VERSION 5.7 ;
  NOWIREEXTENSIONATPIN ON ;
  DIVIDERCHAR "/" ;
  BUSBITCHARS "[]" ;
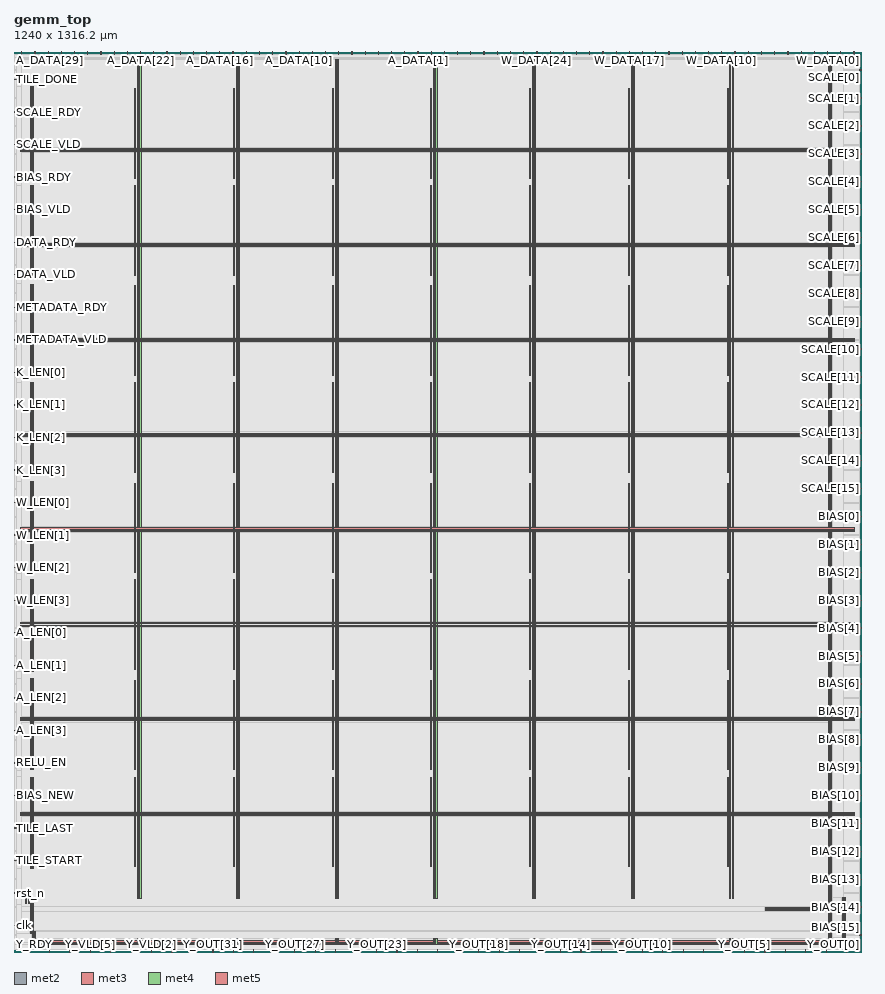
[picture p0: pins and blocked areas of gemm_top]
MACRO gemm_top
  CLASS BLOCK ;
  FOREIGN gemm_top ;
  ORIGIN 0.000 0.000 ;
  SIZE 1240.000 BY 1316.200 ;
  PIN A_DATA[0]
    DIRECTION INPUT ;
    USE SIGNAL ;
    ANTENNAGATEAREA 0.213000 ;
    PORT
      LAYER met2 ;
        RECT 610.050 1312.200 610.330 1316.200 ;
    END
  END A_DATA[0]
  PIN A_DATA[10]
    DIRECTION INPUT ;
    USE SIGNAL ;
    ANTENNAGATEAREA 0.426000 ;
    PORT
      LAYER met2 ;
        RECT 416.850 1312.200 417.130 1316.200 ;
    END
  END A_DATA[10]
  PIN A_DATA[11]
    DIRECTION INPUT ;
    USE SIGNAL ;
    ANTENNAGATEAREA 0.426000 ;
    PORT
      LAYER met2 ;
        RECT 397.530 1312.200 397.810 1316.200 ;
    END
  END A_DATA[11]
  PIN A_DATA[12]
    DIRECTION INPUT ;
    USE SIGNAL ;
    ANTENNAGATEAREA 0.426000 ;
    PORT
      LAYER met2 ;
        RECT 378.210 1312.200 378.490 1316.200 ;
    END
  END A_DATA[12]
  PIN A_DATA[13]
    DIRECTION INPUT ;
    USE SIGNAL ;
    ANTENNAGATEAREA 0.426000 ;
    PORT
      LAYER met2 ;
        RECT 358.890 1312.200 359.170 1316.200 ;
    END
  END A_DATA[13]
  PIN A_DATA[14]
    DIRECTION INPUT ;
    USE SIGNAL ;
    ANTENNAGATEAREA 0.426000 ;
    PORT
      LAYER met2 ;
        RECT 339.570 1312.200 339.850 1316.200 ;
    END
  END A_DATA[14]
  PIN A_DATA[15]
    DIRECTION INPUT ;
    USE SIGNAL ;
    ANTENNAGATEAREA 0.426000 ;
    PORT
      LAYER met2 ;
        RECT 320.250 1312.200 320.530 1316.200 ;
    END
  END A_DATA[15]
  PIN A_DATA[16]
    DIRECTION INPUT ;
    USE SIGNAL ;
    ANTENNAGATEAREA 0.426000 ;
    PORT
      LAYER met2 ;
        RECT 300.930 1312.200 301.210 1316.200 ;
    END
  END A_DATA[16]
  PIN A_DATA[17]
    DIRECTION INPUT ;
    USE SIGNAL ;
    ANTENNAGATEAREA 0.426000 ;
    PORT
      LAYER met2 ;
        RECT 281.610 1312.200 281.890 1316.200 ;
    END
  END A_DATA[17]
  PIN A_DATA[18]
    DIRECTION INPUT ;
    USE SIGNAL ;
    ANTENNAGATEAREA 0.426000 ;
    PORT
      LAYER met2 ;
        RECT 262.290 1312.200 262.570 1316.200 ;
    END
  END A_DATA[18]
  PIN A_DATA[19]
    DIRECTION INPUT ;
    USE SIGNAL ;
    ANTENNAGATEAREA 0.426000 ;
    PORT
      LAYER met2 ;
        RECT 242.970 1312.200 243.250 1316.200 ;
    END
  END A_DATA[19]
  PIN A_DATA[1]
    DIRECTION INPUT ;
    USE SIGNAL ;
    ANTENNAGATEAREA 0.213000 ;
    PORT
      LAYER met2 ;
        RECT 590.730 1312.200 591.010 1316.200 ;
    END
  END A_DATA[1]
  PIN A_DATA[20]
    DIRECTION INPUT ;
    USE SIGNAL ;
    ANTENNAGATEAREA 0.426000 ;
    PORT
      LAYER met2 ;
        RECT 223.650 1312.200 223.930 1316.200 ;
    END
  END A_DATA[20]
  PIN A_DATA[21]
    DIRECTION INPUT ;
    USE SIGNAL ;
    ANTENNAGATEAREA 0.426000 ;
    PORT
      LAYER met2 ;
        RECT 204.330 1312.200 204.610 1316.200 ;
    END
  END A_DATA[21]
  PIN A_DATA[22]
    DIRECTION INPUT ;
    USE SIGNAL ;
    ANTENNAGATEAREA 0.426000 ;
    PORT
      LAYER met2 ;
        RECT 185.010 1312.200 185.290 1316.200 ;
    END
  END A_DATA[22]
  PIN A_DATA[23]
    DIRECTION INPUT ;
    USE SIGNAL ;
    ANTENNAGATEAREA 0.426000 ;
    PORT
      LAYER met2 ;
        RECT 165.690 1312.200 165.970 1316.200 ;
    END
  END A_DATA[23]
  PIN A_DATA[24]
    DIRECTION INPUT ;
    USE SIGNAL ;
    ANTENNAGATEAREA 0.742500 ;
    PORT
      LAYER met2 ;
        RECT 146.370 1312.200 146.650 1316.200 ;
    END
  END A_DATA[24]
  PIN A_DATA[25]
    DIRECTION INPUT ;
    USE SIGNAL ;
    ANTENNAGATEAREA 0.742500 ;
    PORT
      LAYER met2 ;
        RECT 127.050 1312.200 127.330 1316.200 ;
    END
  END A_DATA[25]
  PIN A_DATA[26]
    DIRECTION INPUT ;
    USE SIGNAL ;
    ANTENNAGATEAREA 0.495000 ;
    PORT
      LAYER met2 ;
        RECT 107.730 1312.200 108.010 1316.200 ;
    END
  END A_DATA[26]
  PIN A_DATA[27]
    DIRECTION INPUT ;
    USE SIGNAL ;
    ANTENNAGATEAREA 0.495000 ;
    PORT
      LAYER met2 ;
        RECT 88.410 1312.200 88.690 1316.200 ;
    END
  END A_DATA[27]
  PIN A_DATA[28]
    DIRECTION INPUT ;
    USE SIGNAL ;
    ANTENNAGATEAREA 0.742500 ;
    PORT
      LAYER met2 ;
        RECT 69.090 1312.200 69.370 1316.200 ;
    END
  END A_DATA[28]
  PIN A_DATA[29]
    DIRECTION INPUT ;
    USE SIGNAL ;
    ANTENNAGATEAREA 0.742500 ;
    PORT
      LAYER met2 ;
        RECT 49.770 1312.200 50.050 1316.200 ;
    END
  END A_DATA[29]
  PIN A_DATA[2]
    DIRECTION INPUT ;
    USE SIGNAL ;
    ANTENNAGATEAREA 0.213000 ;
    PORT
      LAYER met2 ;
        RECT 571.410 1312.200 571.690 1316.200 ;
    END
  END A_DATA[2]
  PIN A_DATA[30]
    DIRECTION INPUT ;
    USE SIGNAL ;
    ANTENNAGATEAREA 0.742500 ;
    PORT
      LAYER met2 ;
        RECT 30.450 1312.200 30.730 1316.200 ;
    END
  END A_DATA[30]
  PIN A_DATA[31]
    DIRECTION INPUT ;
    USE SIGNAL ;
    ANTENNAGATEAREA 0.742500 ;
    PORT
      LAYER met2 ;
        RECT 11.130 1312.200 11.410 1316.200 ;
    END
  END A_DATA[31]
  PIN A_DATA[3]
    DIRECTION INPUT ;
    USE SIGNAL ;
    ANTENNAGATEAREA 0.213000 ;
    PORT
      LAYER met2 ;
        RECT 552.090 1312.200 552.370 1316.200 ;
    END
  END A_DATA[3]
  PIN A_DATA[4]
    DIRECTION INPUT ;
    USE SIGNAL ;
    ANTENNAGATEAREA 0.247500 ;
    PORT
      LAYER met2 ;
        RECT 532.770 1312.200 533.050 1316.200 ;
    END
  END A_DATA[4]
  PIN A_DATA[5]
    DIRECTION INPUT ;
    USE SIGNAL ;
    ANTENNAGATEAREA 0.247500 ;
    PORT
      LAYER met2 ;
        RECT 513.450 1312.200 513.730 1316.200 ;
    END
  END A_DATA[5]
  PIN A_DATA[6]
    DIRECTION INPUT ;
    USE SIGNAL ;
    ANTENNAGATEAREA 0.213000 ;
    PORT
      LAYER met2 ;
        RECT 494.130 1312.200 494.410 1316.200 ;
    END
  END A_DATA[6]
  PIN A_DATA[7]
    DIRECTION INPUT ;
    USE SIGNAL ;
    ANTENNAGATEAREA 0.213000 ;
    PORT
      LAYER met2 ;
        RECT 474.810 1312.200 475.090 1316.200 ;
    END
  END A_DATA[7]
  PIN A_DATA[8]
    DIRECTION INPUT ;
    USE SIGNAL ;
    ANTENNAGATEAREA 0.426000 ;
    PORT
      LAYER met2 ;
        RECT 455.490 1312.200 455.770 1316.200 ;
    END
  END A_DATA[8]
  PIN A_DATA[9]
    DIRECTION INPUT ;
    USE SIGNAL ;
    ANTENNAGATEAREA 0.426000 ;
    PORT
      LAYER met2 ;
        RECT 436.170 1312.200 436.450 1316.200 ;
    END
  END A_DATA[9]
  PIN A_LEN[0]
    DIRECTION INPUT ;
    USE SIGNAL ;
    ANTENNAGATEAREA 0.213000 ;
    PORT
      LAYER met3 ;
        RECT 0.000 466.520 4.000 467.120 ;
    END
  END A_LEN[0]
  PIN A_LEN[1]
    DIRECTION INPUT ;
    USE SIGNAL ;
    ANTENNAGATEAREA 0.159000 ;
    PORT
      LAYER met3 ;
        RECT 0.000 418.920 4.000 419.520 ;
    END
  END A_LEN[1]
  PIN A_LEN[2]
    DIRECTION INPUT ;
    USE SIGNAL ;
    ANTENNAGATEAREA 0.213000 ;
    PORT
      LAYER met3 ;
        RECT 0.000 371.320 4.000 371.920 ;
    END
  END A_LEN[2]
  PIN A_LEN[3]
    DIRECTION INPUT ;
    USE SIGNAL ;
    ANTENNAGATEAREA 0.213000 ;
    PORT
      LAYER met3 ;
        RECT 0.000 323.720 4.000 324.320 ;
    END
  END A_LEN[3]
  PIN BIAS[0]
    DIRECTION INPUT ;
    USE SIGNAL ;
    ANTENNAGATEAREA 0.990000 ;
    PORT
      LAYER met3 ;
        RECT 1236.000 636.520 1240.000 637.120 ;
    END
  END BIAS[0]
  PIN BIAS[10]
    DIRECTION INPUT ;
    USE SIGNAL ;
    ANTENNAGATEAREA 0.990000 ;
    PORT
      LAYER met3 ;
        RECT 1236.000 228.520 1240.000 229.120 ;
    END
  END BIAS[10]
  PIN BIAS[11]
    DIRECTION INPUT ;
    USE SIGNAL ;
    ANTENNAGATEAREA 0.990000 ;
    PORT
      LAYER met3 ;
        RECT 1236.000 187.720 1240.000 188.320 ;
    END
  END BIAS[11]
  PIN BIAS[12]
    DIRECTION INPUT ;
    USE SIGNAL ;
    ANTENNAGATEAREA 0.990000 ;
    PORT
      LAYER met3 ;
        RECT 1236.000 146.920 1240.000 147.520 ;
    END
  END BIAS[12]
  PIN BIAS[13]
    DIRECTION INPUT ;
    USE SIGNAL ;
    ANTENNAGATEAREA 0.990000 ;
    PORT
      LAYER met3 ;
        RECT 1236.000 106.120 1240.000 106.720 ;
    END
  END BIAS[13]
  PIN BIAS[14]
    DIRECTION INPUT ;
    USE SIGNAL ;
    ANTENNAGATEAREA 0.990000 ;
    PORT
      LAYER met3 ;
        RECT 1236.000 65.320 1240.000 65.920 ;
    END
  END BIAS[14]
  PIN BIAS[15]
    DIRECTION INPUT ;
    USE SIGNAL ;
    ANTENNAGATEAREA 0.990000 ;
    PORT
      LAYER met3 ;
        RECT 1236.000 24.520 1240.000 25.120 ;
    END
  END BIAS[15]
  PIN BIAS[1]
    DIRECTION INPUT ;
    USE SIGNAL ;
    ANTENNAGATEAREA 0.990000 ;
    PORT
      LAYER met3 ;
        RECT 1236.000 595.720 1240.000 596.320 ;
    END
  END BIAS[1]
  PIN BIAS[2]
    DIRECTION INPUT ;
    USE SIGNAL ;
    ANTENNAGATEAREA 0.990000 ;
    PORT
      LAYER met3 ;
        RECT 1236.000 554.920 1240.000 555.520 ;
    END
  END BIAS[2]
  PIN BIAS[3]
    DIRECTION INPUT ;
    USE SIGNAL ;
    ANTENNAGATEAREA 0.990000 ;
    PORT
      LAYER met3 ;
        RECT 1236.000 514.120 1240.000 514.720 ;
    END
  END BIAS[3]
  PIN BIAS[4]
    DIRECTION INPUT ;
    USE SIGNAL ;
    ANTENNAGATEAREA 0.990000 ;
    PORT
      LAYER met3 ;
        RECT 1236.000 473.320 1240.000 473.920 ;
    END
  END BIAS[4]
  PIN BIAS[5]
    DIRECTION INPUT ;
    USE SIGNAL ;
    ANTENNAGATEAREA 0.990000 ;
    PORT
      LAYER met3 ;
        RECT 1236.000 432.520 1240.000 433.120 ;
    END
  END BIAS[5]
  PIN BIAS[6]
    DIRECTION INPUT ;
    USE SIGNAL ;
    ANTENNAGATEAREA 0.990000 ;
    PORT
      LAYER met3 ;
        RECT 1236.000 391.720 1240.000 392.320 ;
    END
  END BIAS[6]
  PIN BIAS[7]
    DIRECTION INPUT ;
    USE SIGNAL ;
    ANTENNAGATEAREA 0.990000 ;
    PORT
      LAYER met3 ;
        RECT 1236.000 350.920 1240.000 351.520 ;
    END
  END BIAS[7]
  PIN BIAS[8]
    DIRECTION INPUT ;
    USE SIGNAL ;
    ANTENNAGATEAREA 0.990000 ;
    PORT
      LAYER met3 ;
        RECT 1236.000 310.120 1240.000 310.720 ;
    END
  END BIAS[8]
  PIN BIAS[9]
    DIRECTION INPUT ;
    USE SIGNAL ;
    ANTENNAGATEAREA 0.990000 ;
    PORT
      LAYER met3 ;
        RECT 1236.000 269.320 1240.000 269.920 ;
    END
  END BIAS[9]
  PIN BIAS_NEW
    DIRECTION INPUT ;
    USE SIGNAL ;
    ANTENNAGATEAREA 0.213000 ;
    PORT
      LAYER met3 ;
        RECT 0.000 228.520 4.000 229.120 ;
    END
  END BIAS_NEW
  PIN BIAS_RDY
    DIRECTION OUTPUT ;
    USE SIGNAL ;
    ANTENNADIFFAREA 0.340600 ;
    PORT
      LAYER met3 ;
        RECT 0.000 1132.920 4.000 1133.520 ;
    END
  END BIAS_RDY
  PIN BIAS_VLD
    DIRECTION INPUT ;
    USE SIGNAL ;
    ANTENNAGATEAREA 0.213000 ;
    PORT
      LAYER met3 ;
        RECT 0.000 1085.320 4.000 1085.920 ;
    END
  END BIAS_VLD
  PIN DATA_RDY
    DIRECTION OUTPUT ;
    USE SIGNAL ;
    ANTENNADIFFAREA 0.340600 ;
    PORT
      LAYER met3 ;
        RECT 0.000 1037.720 4.000 1038.320 ;
    END
  END DATA_RDY
  PIN DATA_VLD
    DIRECTION INPUT ;
    USE SIGNAL ;
    ANTENNAGATEAREA 0.159000 ;
    PORT
      LAYER met3 ;
        RECT 0.000 990.120 4.000 990.720 ;
    END
  END DATA_VLD
  PIN K_LEN[0]
    DIRECTION INPUT ;
    USE SIGNAL ;
    ANTENNAGATEAREA 0.159000 ;
    PORT
      LAYER met3 ;
        RECT 0.000 847.320 4.000 847.920 ;
    END
  END K_LEN[0]
  PIN K_LEN[1]
    DIRECTION INPUT ;
    USE SIGNAL ;
    ANTENNAGATEAREA 0.159000 ;
    PORT
      LAYER met3 ;
        RECT 0.000 799.720 4.000 800.320 ;
    END
  END K_LEN[1]
  PIN K_LEN[2]
    DIRECTION INPUT ;
    USE SIGNAL ;
    ANTENNAGATEAREA 0.213000 ;
    PORT
      LAYER met3 ;
        RECT 0.000 752.120 4.000 752.720 ;
    END
  END K_LEN[2]
  PIN K_LEN[3]
    DIRECTION INPUT ;
    USE SIGNAL ;
    ANTENNAGATEAREA 0.213000 ;
    PORT
      LAYER met3 ;
        RECT 0.000 704.520 4.000 705.120 ;
    END
  END K_LEN[3]
  PIN METADATA_RDY
    DIRECTION OUTPUT ;
    USE SIGNAL ;
    ANTENNADIFFAREA 0.340600 ;
    PORT
      LAYER met3 ;
        RECT 0.000 942.520 4.000 943.120 ;
    END
  END METADATA_RDY
  PIN METADATA_VLD
    DIRECTION INPUT ;
    USE SIGNAL ;
    ANTENNAGATEAREA 0.213000 ;
    PORT
      LAYER met3 ;
        RECT 0.000 894.920 4.000 895.520 ;
    END
  END METADATA_VLD
  PIN RELU_EN
    DIRECTION INPUT ;
    USE SIGNAL ;
    ANTENNAGATEAREA 0.196500 ;
    PORT
      LAYER met3 ;
        RECT 0.000 276.120 4.000 276.720 ;
    END
  END RELU_EN
  PIN SCALE[0]
    DIRECTION INPUT ;
    USE SIGNAL ;
    ANTENNAGATEAREA 0.742500 ;
    PORT
      LAYER met3 ;
        RECT 1236.000 1289.320 1240.000 1289.920 ;
    END
  END SCALE[0]
  PIN SCALE[10]
    DIRECTION INPUT ;
    USE SIGNAL ;
    ANTENNAGATEAREA 0.247500 ;
    PORT
      LAYER met3 ;
        RECT 1236.000 881.320 1240.000 881.920 ;
    END
  END SCALE[10]
  PIN SCALE[11]
    DIRECTION INPUT ;
    USE SIGNAL ;
    ANTENNAGATEAREA 0.247500 ;
    PORT
      LAYER met3 ;
        RECT 1236.000 840.520 1240.000 841.120 ;
    END
  END SCALE[11]
  PIN SCALE[12]
    DIRECTION INPUT ;
    USE SIGNAL ;
    ANTENNAGATEAREA 0.247500 ;
    PORT
      LAYER met3 ;
        RECT 1236.000 799.720 1240.000 800.320 ;
    END
  END SCALE[12]
  PIN SCALE[13]
    DIRECTION INPUT ;
    USE SIGNAL ;
    ANTENNAGATEAREA 0.247500 ;
    PORT
      LAYER met3 ;
        RECT 1236.000 758.920 1240.000 759.520 ;
    END
  END SCALE[13]
  PIN SCALE[14]
    DIRECTION INPUT ;
    USE SIGNAL ;
    ANTENNAGATEAREA 0.247500 ;
    PORT
      LAYER met3 ;
        RECT 1236.000 718.120 1240.000 718.720 ;
    END
  END SCALE[14]
  PIN SCALE[15]
    DIRECTION INPUT ;
    USE SIGNAL ;
    ANTENNAGATEAREA 0.159000 ;
    PORT
      LAYER met3 ;
        RECT 1236.000 677.320 1240.000 677.920 ;
    END
  END SCALE[15]
  PIN SCALE[1]
    DIRECTION INPUT ;
    USE SIGNAL ;
    ANTENNAGATEAREA 0.495000 ;
    PORT
      LAYER met3 ;
        RECT 1236.000 1248.520 1240.000 1249.120 ;
    END
  END SCALE[1]
  PIN SCALE[2]
    DIRECTION INPUT ;
    USE SIGNAL ;
    ANTENNAGATEAREA 0.495000 ;
    PORT
      LAYER met3 ;
        RECT 1236.000 1207.720 1240.000 1208.320 ;
    END
  END SCALE[2]
  PIN SCALE[3]
    DIRECTION INPUT ;
    USE SIGNAL ;
    ANTENNAGATEAREA 0.495000 ;
    PORT
      LAYER met3 ;
        RECT 1236.000 1166.920 1240.000 1167.520 ;
    END
  END SCALE[3]
  PIN SCALE[4]
    DIRECTION INPUT ;
    USE SIGNAL ;
    ANTENNAGATEAREA 0.495000 ;
    PORT
      LAYER met3 ;
        RECT 1236.000 1126.120 1240.000 1126.720 ;
    END
  END SCALE[4]
  PIN SCALE[5]
    DIRECTION INPUT ;
    USE SIGNAL ;
    ANTENNAGATEAREA 0.426000 ;
    PORT
      LAYER met3 ;
        RECT 1236.000 1085.320 1240.000 1085.920 ;
    END
  END SCALE[5]
  PIN SCALE[6]
    DIRECTION INPUT ;
    USE SIGNAL ;
    ANTENNAGATEAREA 0.426000 ;
    PORT
      LAYER met3 ;
        RECT 1236.000 1044.520 1240.000 1045.120 ;
    END
  END SCALE[6]
  PIN SCALE[7]
    DIRECTION INPUT ;
    USE SIGNAL ;
    ANTENNAGATEAREA 0.426000 ;
    PORT
      LAYER met3 ;
        RECT 1236.000 1003.720 1240.000 1004.320 ;
    END
  END SCALE[7]
  PIN SCALE[8]
    DIRECTION INPUT ;
    USE SIGNAL ;
    ANTENNAGATEAREA 0.426000 ;
    PORT
      LAYER met3 ;
        RECT 1236.000 962.920 1240.000 963.520 ;
    END
  END SCALE[8]
  PIN SCALE[9]
    DIRECTION INPUT ;
    USE SIGNAL ;
    ANTENNAGATEAREA 0.426000 ;
    PORT
      LAYER met3 ;
        RECT 1236.000 922.120 1240.000 922.720 ;
    END
  END SCALE[9]
  PIN SCALE_RDY
    DIRECTION OUTPUT ;
    USE SIGNAL ;
    ANTENNADIFFAREA 0.340600 ;
    PORT
      LAYER met3 ;
        RECT 0.000 1228.120 4.000 1228.720 ;
    END
  END SCALE_RDY
  PIN SCALE_VLD
    DIRECTION INPUT ;
    USE SIGNAL ;
    ANTENNAGATEAREA 0.742500 ;
    PORT
      LAYER met3 ;
        RECT 0.000 1180.520 4.000 1181.120 ;
    END
  END SCALE_VLD
  PIN TILE_DONE
    DIRECTION OUTPUT ;
    USE SIGNAL ;
    ANTENNADIFFAREA 0.340600 ;
    PORT
      LAYER met3 ;
        RECT 0.000 1275.720 4.000 1276.320 ;
    END
  END TILE_DONE
  PIN TILE_LAST
    DIRECTION INPUT ;
    USE SIGNAL ;
    ANTENNAGATEAREA 0.213000 ;
    PORT
      LAYER met3 ;
        RECT 0.000 180.920 4.000 181.520 ;
    END
  END TILE_LAST
  PIN TILE_START
    DIRECTION INPUT ;
    USE SIGNAL ;
    ANTENNAGATEAREA 0.126000 ;
    PORT
      LAYER met3 ;
        RECT 0.000 133.320 4.000 133.920 ;
    END
  END TILE_START
  PIN VGND
    DIRECTION INOUT ;
    USE GROUND ;
    PORT
      LAYER met4 ;
        RECT 184.155 10.640 185.755 19.115 ;
    END
    PORT
      LAYER met4 ;
        RECT 184.155 78.125 185.755 1305.840 ;
    END
    PORT
      LAYER met4 ;
        RECT 328.485 10.640 330.085 19.115 ;
    END
    PORT
      LAYER met4 ;
        RECT 328.485 78.125 330.085 1305.840 ;
    END
    PORT
      LAYER met4 ;
        RECT 472.815 10.640 474.415 19.115 ;
    END
    PORT
      LAYER met4 ;
        RECT 472.815 78.125 474.415 1305.840 ;
    END
    PORT
      LAYER met4 ;
        RECT 617.145 10.640 618.745 19.115 ;
    END
    PORT
      LAYER met4 ;
        RECT 617.145 78.125 618.745 1305.840 ;
    END
    PORT
      LAYER met4 ;
        RECT 761.475 10.640 763.075 19.115 ;
    END
    PORT
      LAYER met4 ;
        RECT 761.475 78.125 763.075 1305.840 ;
    END
    PORT
      LAYER met4 ;
        RECT 905.805 10.640 907.405 19.115 ;
    END
    PORT
      LAYER met4 ;
        RECT 905.805 78.125 907.405 1305.840 ;
    END
    PORT
      LAYER met4 ;
        RECT 1050.135 10.640 1051.735 19.115 ;
    END
    PORT
      LAYER met4 ;
        RECT 1050.135 78.125 1051.735 1305.840 ;
    END
    PORT
      LAYER met4 ;
        RECT 1194.465 10.640 1196.065 1305.840 ;
    END
    PORT
      LAYER met5 ;
        RECT 9.880 202.420 1229.820 204.020 ;
    END
    PORT
      LAYER met5 ;
        RECT 9.880 341.140 1229.820 342.740 ;
    END
    PORT
      LAYER met5 ;
        RECT 9.880 479.860 1229.820 481.460 ;
    END
    PORT
      LAYER met5 ;
        RECT 9.880 618.580 1229.820 620.180 ;
    END
    PORT
      LAYER met5 ;
        RECT 9.880 757.300 1229.820 758.900 ;
    END
    PORT
      LAYER met5 ;
        RECT 9.880 896.020 1229.820 897.620 ;
    END
    PORT
      LAYER met5 ;
        RECT 9.880 1034.740 1229.820 1036.340 ;
    END
    PORT
      LAYER met5 ;
        RECT 9.880 1173.460 1229.820 1175.060 ;
    END
    PORT
      LAYER met5 ;
        RECT 1099.700 63.700 1229.820 65.300 ;
    END
    PORT
      LAYER met4 ;
        RECT 30.020 13.360 31.620 30.160 ;
    END
    PORT
      LAYER met4 ;
        RECT 27.260 30.460 28.860 70.480 ;
    END
    PORT
      LAYER met4 ;
        RECT 176.300 124.880 177.900 255.920 ;
    END
    PORT
      LAYER met4 ;
        RECT 320.740 266.320 322.340 397.360 ;
    END
    PORT
      LAYER met4 ;
        RECT 465.180 413.200 466.780 544.240 ;
    END
    PORT
      LAYER met4 ;
        RECT 609.620 554.640 611.220 685.680 ;
    END
    PORT
      LAYER met4 ;
        RECT 754.060 701.520 755.660 832.560 ;
    END
    PORT
      LAYER met4 ;
        RECT 898.500 842.960 900.100 974.000 ;
    END
    PORT
      LAYER met4 ;
        RECT 1042.940 989.840 1044.540 1120.880 ;
    END
    PORT
      LAYER met4 ;
        RECT 20.820 70.480 22.420 87.280 ;
    END
    PORT
      LAYER met4 ;
        RECT 27.260 122.160 28.860 255.920 ;
    END
    PORT
      LAYER met4 ;
        RECT 176.300 266.320 177.900 397.360 ;
    END
    PORT
      LAYER met4 ;
        RECT 320.740 413.200 322.340 544.240 ;
    END
    PORT
      LAYER met4 ;
        RECT 465.180 554.640 466.780 685.680 ;
    END
    PORT
      LAYER met4 ;
        RECT 609.620 701.520 611.220 832.560 ;
    END
    PORT
      LAYER met4 ;
        RECT 754.060 842.960 755.660 974.000 ;
    END
    PORT
      LAYER met4 ;
        RECT 898.500 989.840 900.100 1120.880 ;
    END
    PORT
      LAYER met4 ;
        RECT 1042.940 1131.280 1044.540 1262.320 ;
    END
    PORT
      LAYER met4 ;
        RECT 1214.980 21.520 1216.580 79.120 ;
    END
    PORT
      LAYER met4 ;
        RECT 27.260 266.320 28.860 400.080 ;
    END
    PORT
      LAYER met4 ;
        RECT 176.300 413.200 177.900 544.240 ;
    END
    PORT
      LAYER met4 ;
        RECT 320.740 124.880 322.340 255.920 ;
    END
    PORT
      LAYER met4 ;
        RECT 465.180 701.520 466.780 832.560 ;
    END
    PORT
      LAYER met4 ;
        RECT 609.620 842.960 611.220 974.000 ;
    END
    PORT
      LAYER met4 ;
        RECT 754.060 554.640 755.660 685.680 ;
    END
    PORT
      LAYER met4 ;
        RECT 898.500 1131.280 900.100 1262.320 ;
    END
    PORT
      LAYER met4 ;
        RECT 27.260 410.480 28.860 544.240 ;
    END
    PORT
      LAYER met4 ;
        RECT 176.300 554.640 177.900 685.680 ;
    END
    PORT
      LAYER met4 ;
        RECT 320.740 701.520 322.340 832.560 ;
    END
    PORT
      LAYER met4 ;
        RECT 465.180 124.880 466.780 255.920 ;
    END
    PORT
      LAYER met4 ;
        RECT 609.620 266.320 611.220 397.360 ;
    END
    PORT
      LAYER met4 ;
        RECT 754.060 989.840 755.660 1120.880 ;
    END
    PORT
      LAYER met4 ;
        RECT 1042.940 842.960 1044.540 974.000 ;
    END
    PORT
      LAYER met4 ;
        RECT 27.260 554.640 28.860 688.400 ;
    END
    PORT
      LAYER met4 ;
        RECT 176.300 701.520 177.900 832.560 ;
    END
    PORT
      LAYER met4 ;
        RECT 320.740 842.960 322.340 974.000 ;
    END
    PORT
      LAYER met4 ;
        RECT 465.180 266.320 466.780 397.360 ;
    END
    PORT
      LAYER met4 ;
        RECT 609.620 124.880 611.220 255.920 ;
    END
    PORT
      LAYER met4 ;
        RECT 754.060 413.200 755.660 544.240 ;
    END
    PORT
      LAYER met4 ;
        RECT 27.260 698.800 28.860 832.560 ;
    END
    PORT
      LAYER met4 ;
        RECT 176.300 842.960 177.900 974.000 ;
    END
    PORT
      LAYER met4 ;
        RECT 320.740 554.640 322.340 685.680 ;
    END
    PORT
      LAYER met4 ;
        RECT 465.180 989.840 466.780 1120.880 ;
    END
    PORT
      LAYER met4 ;
        RECT 609.620 413.200 611.220 544.240 ;
    END
    PORT
      LAYER met4 ;
        RECT 754.060 124.880 755.660 255.920 ;
    END
    PORT
      LAYER met4 ;
        RECT 898.500 266.320 900.100 397.360 ;
    END
    PORT
      LAYER met4 ;
        RECT 27.260 842.960 28.860 976.720 ;
    END
    PORT
      LAYER met4 ;
        RECT 176.300 989.840 177.900 1120.880 ;
    END
    PORT
      LAYER met4 ;
        RECT 320.740 1131.280 322.340 1262.320 ;
    END
    PORT
      LAYER met4 ;
        RECT 754.060 266.320 755.660 397.360 ;
    END
    PORT
      LAYER met4 ;
        RECT 898.500 124.880 900.100 255.920 ;
    END
    PORT
      LAYER met4 ;
        RECT 1042.940 413.200 1044.540 544.240 ;
    END
    PORT
      LAYER met4 ;
        RECT 27.260 987.120 28.860 1120.880 ;
    END
    PORT
      LAYER met4 ;
        RECT 176.300 1131.280 177.900 1262.320 ;
    END
    PORT
      LAYER met4 ;
        RECT 465.180 842.960 466.780 974.000 ;
    END
    PORT
      LAYER met4 ;
        RECT 898.500 413.200 900.100 544.240 ;
    END
    PORT
      LAYER met4 ;
        RECT 1042.940 124.880 1044.540 255.920 ;
    END
    PORT
      LAYER met4 ;
        RECT 27.260 1131.280 28.860 1265.040 ;
    END
    PORT
      LAYER met4 ;
        RECT 320.740 989.840 322.340 1120.880 ;
    END
    PORT
      LAYER met4 ;
        RECT 898.500 554.640 900.100 685.680 ;
    END
    PORT
      LAYER met4 ;
        RECT 1042.940 266.320 1044.540 397.360 ;
    END
    PORT
      LAYER met4 ;
        RECT 465.180 1131.280 466.780 1262.320 ;
    END
    PORT
      LAYER met4 ;
        RECT 609.620 989.840 611.220 1120.880 ;
    END
    PORT
      LAYER met4 ;
        RECT 898.500 701.520 900.100 832.560 ;
    END
    PORT
      LAYER met4 ;
        RECT 1042.940 554.640 1044.540 685.680 ;
    END
    PORT
      LAYER met4 ;
        RECT 609.620 1131.280 611.220 1262.320 ;
    END
    PORT
      LAYER met4 ;
        RECT 1042.940 701.520 1044.540 832.560 ;
    END
    PORT
      LAYER met4 ;
        RECT 754.060 1131.280 755.660 1262.320 ;
    END
    PORT
      LAYER met5 ;
        RECT 36.525 14.500 1196.065 16.100 ;
    END
  END VGND
  PIN VPWR
    DIRECTION INOUT ;
    USE POWER ;
    PORT
      LAYER met4 ;
        RECT 180.855 10.640 182.455 19.115 ;
    END
    PORT
      LAYER met4 ;
        RECT 180.855 78.125 182.455 1305.840 ;
    END
    PORT
      LAYER met4 ;
        RECT 325.185 10.640 326.785 19.115 ;
    END
    PORT
      LAYER met4 ;
        RECT 325.185 78.125 326.785 1305.840 ;
    END
    PORT
      LAYER met4 ;
        RECT 469.515 10.640 471.115 19.115 ;
    END
    PORT
      LAYER met4 ;
        RECT 469.515 78.125 471.115 1305.840 ;
    END
    PORT
      LAYER met4 ;
        RECT 613.845 10.640 615.445 19.115 ;
    END
    PORT
      LAYER met4 ;
        RECT 613.845 78.125 615.445 1305.840 ;
    END
    PORT
      LAYER met4 ;
        RECT 758.175 10.640 759.775 19.115 ;
    END
    PORT
      LAYER met4 ;
        RECT 758.175 78.125 759.775 1305.840 ;
    END
    PORT
      LAYER met4 ;
        RECT 902.505 10.640 904.105 19.115 ;
    END
    PORT
      LAYER met4 ;
        RECT 902.505 78.125 904.105 1305.840 ;
    END
    PORT
      LAYER met4 ;
        RECT 1046.835 10.640 1048.435 19.115 ;
    END
    PORT
      LAYER met4 ;
        RECT 1046.835 78.125 1048.435 1305.840 ;
    END
    PORT
      LAYER met4 ;
        RECT 1191.165 10.640 1192.765 1305.840 ;
    END
    PORT
      LAYER met5 ;
        RECT 9.880 199.120 1229.820 200.720 ;
    END
    PORT
      LAYER met5 ;
        RECT 9.880 337.840 1229.820 339.440 ;
    END
    PORT
      LAYER met5 ;
        RECT 9.880 476.560 1229.820 478.160 ;
    END
    PORT
      LAYER met5 ;
        RECT 9.880 615.280 1229.820 616.880 ;
    END
    PORT
      LAYER met5 ;
        RECT 9.880 754.000 1229.820 755.600 ;
    END
    PORT
      LAYER met5 ;
        RECT 9.880 892.720 1229.820 894.320 ;
    END
    PORT
      LAYER met5 ;
        RECT 9.880 1031.440 1229.820 1033.040 ;
    END
    PORT
      LAYER met5 ;
        RECT 9.880 1170.160 1229.820 1171.760 ;
    END
    PORT
      LAYER met5 ;
        RECT 1099.700 60.400 1229.820 62.000 ;
    END
    PORT
      LAYER met4 ;
        RECT 26.340 13.360 27.940 30.160 ;
    END
    PORT
      LAYER met4 ;
        RECT 23.580 26.960 25.180 70.480 ;
    END
    PORT
      LAYER met4 ;
        RECT 17.140 70.480 18.740 87.280 ;
    END
    PORT
      LAYER met4 ;
        RECT 23.580 122.160 25.180 255.920 ;
    END
    PORT
      LAYER met4 ;
        RECT 1211.300 21.520 1212.900 79.120 ;
    END
    PORT
      LAYER met4 ;
        RECT 23.580 266.320 25.180 400.080 ;
    END
    PORT
      LAYER met4 ;
        RECT 23.580 410.480 25.180 544.240 ;
    END
    PORT
      LAYER met4 ;
        RECT 23.580 554.640 25.180 688.400 ;
    END
    PORT
      LAYER met4 ;
        RECT 23.580 698.800 25.180 832.560 ;
    END
    PORT
      LAYER met4 ;
        RECT 23.580 842.960 25.180 976.720 ;
    END
    PORT
      LAYER met4 ;
        RECT 23.580 987.120 25.180 1120.880 ;
    END
    PORT
      LAYER met4 ;
        RECT 23.580 1131.280 25.180 1265.040 ;
    END
    PORT
      LAYER met5 ;
        RECT 36.525 11.100 1196.065 12.700 ;
    END
  END VPWR
  PIN W_DATA[0]
    DIRECTION INPUT ;
    USE SIGNAL ;
    ANTENNAGATEAREA 0.495000 ;
    PORT
      LAYER met2 ;
        RECT 1228.290 1312.200 1228.570 1316.200 ;
    END
  END W_DATA[0]
  PIN W_DATA[10]
    DIRECTION INPUT ;
    USE SIGNAL ;
    ANTENNAGATEAREA 0.247500 ;
    PORT
      LAYER met2 ;
        RECT 1035.090 1312.200 1035.370 1316.200 ;
    END
  END W_DATA[10]
  PIN W_DATA[11]
    DIRECTION INPUT ;
    USE SIGNAL ;
    ANTENNAGATEAREA 0.247500 ;
    PORT
      LAYER met2 ;
        RECT 1015.770 1312.200 1016.050 1316.200 ;
    END
  END W_DATA[11]
  PIN W_DATA[12]
    DIRECTION INPUT ;
    USE SIGNAL ;
    ANTENNAGATEAREA 0.213000 ;
    PORT
      LAYER met2 ;
        RECT 996.450 1312.200 996.730 1316.200 ;
    END
  END W_DATA[12]
  PIN W_DATA[13]
    DIRECTION INPUT ;
    USE SIGNAL ;
    ANTENNAGATEAREA 0.213000 ;
    PORT
      LAYER met2 ;
        RECT 977.130 1312.200 977.410 1316.200 ;
    END
  END W_DATA[13]
  PIN W_DATA[14]
    DIRECTION INPUT ;
    USE SIGNAL ;
    ANTENNAGATEAREA 0.159000 ;
    PORT
      LAYER met2 ;
        RECT 957.810 1312.200 958.090 1316.200 ;
    END
  END W_DATA[14]
  PIN W_DATA[15]
    DIRECTION INPUT ;
    USE SIGNAL ;
    ANTENNAGATEAREA 0.159000 ;
    PORT
      LAYER met2 ;
        RECT 938.490 1312.200 938.770 1316.200 ;
    END
  END W_DATA[15]
  PIN W_DATA[16]
    DIRECTION INPUT ;
    USE SIGNAL ;
    ANTENNAGATEAREA 0.213000 ;
    PORT
      LAYER met2 ;
        RECT 919.170 1312.200 919.450 1316.200 ;
    END
  END W_DATA[16]
  PIN W_DATA[17]
    DIRECTION INPUT ;
    USE SIGNAL ;
    ANTENNAGATEAREA 0.159000 ;
    PORT
      LAYER met2 ;
        RECT 899.850 1312.200 900.130 1316.200 ;
    END
  END W_DATA[17]
  PIN W_DATA[18]
    DIRECTION INPUT ;
    USE SIGNAL ;
    ANTENNAGATEAREA 0.213000 ;
    PORT
      LAYER met2 ;
        RECT 880.530 1312.200 880.810 1316.200 ;
    END
  END W_DATA[18]
  PIN W_DATA[19]
    DIRECTION INPUT ;
    USE SIGNAL ;
    ANTENNAGATEAREA 0.213000 ;
    PORT
      LAYER met2 ;
        RECT 861.210 1312.200 861.490 1316.200 ;
    END
  END W_DATA[19]
  PIN W_DATA[1]
    DIRECTION INPUT ;
    USE SIGNAL ;
    ANTENNAGATEAREA 0.495000 ;
    PORT
      LAYER met2 ;
        RECT 1208.970 1312.200 1209.250 1316.200 ;
    END
  END W_DATA[1]
  PIN W_DATA[20]
    DIRECTION INPUT ;
    USE SIGNAL ;
    ANTENNAGATEAREA 0.213000 ;
    PORT
      LAYER met2 ;
        RECT 841.890 1312.200 842.170 1316.200 ;
    END
  END W_DATA[20]
  PIN W_DATA[21]
    DIRECTION INPUT ;
    USE SIGNAL ;
    ANTENNAGATEAREA 0.213000 ;
    PORT
      LAYER met2 ;
        RECT 822.570 1312.200 822.850 1316.200 ;
    END
  END W_DATA[21]
  PIN W_DATA[22]
    DIRECTION INPUT ;
    USE SIGNAL ;
    ANTENNAGATEAREA 0.213000 ;
    PORT
      LAYER met2 ;
        RECT 803.250 1312.200 803.530 1316.200 ;
    END
  END W_DATA[22]
  PIN W_DATA[23]
    DIRECTION INPUT ;
    USE SIGNAL ;
    ANTENNAGATEAREA 0.213000 ;
    PORT
      LAYER met2 ;
        RECT 783.930 1312.200 784.210 1316.200 ;
    END
  END W_DATA[23]
  PIN W_DATA[24]
    DIRECTION INPUT ;
    USE SIGNAL ;
    ANTENNAGATEAREA 0.247500 ;
    PORT
      LAYER met2 ;
        RECT 764.610 1312.200 764.890 1316.200 ;
    END
  END W_DATA[24]
  PIN W_DATA[25]
    DIRECTION INPUT ;
    USE SIGNAL ;
    ANTENNAGATEAREA 0.247500 ;
    PORT
      LAYER met2 ;
        RECT 745.290 1312.200 745.570 1316.200 ;
    END
  END W_DATA[25]
  PIN W_DATA[26]
    DIRECTION INPUT ;
    USE SIGNAL ;
    ANTENNAGATEAREA 0.247500 ;
    PORT
      LAYER met2 ;
        RECT 725.970 1312.200 726.250 1316.200 ;
    END
  END W_DATA[26]
  PIN W_DATA[27]
    DIRECTION INPUT ;
    USE SIGNAL ;
    ANTENNAGATEAREA 0.247500 ;
    PORT
      LAYER met2 ;
        RECT 706.650 1312.200 706.930 1316.200 ;
    END
  END W_DATA[27]
  PIN W_DATA[28]
    DIRECTION INPUT ;
    USE SIGNAL ;
    ANTENNAGATEAREA 0.247500 ;
    PORT
      LAYER met2 ;
        RECT 687.330 1312.200 687.610 1316.200 ;
    END
  END W_DATA[28]
  PIN W_DATA[29]
    DIRECTION INPUT ;
    USE SIGNAL ;
    ANTENNAGATEAREA 0.426000 ;
    PORT
      LAYER met2 ;
        RECT 668.010 1312.200 668.290 1316.200 ;
    END
  END W_DATA[29]
  PIN W_DATA[2]
    DIRECTION INPUT ;
    USE SIGNAL ;
    ANTENNAGATEAREA 0.426000 ;
    PORT
      LAYER met2 ;
        RECT 1189.650 1312.200 1189.930 1316.200 ;
    END
  END W_DATA[2]
  PIN W_DATA[30]
    DIRECTION INPUT ;
    USE SIGNAL ;
    ANTENNAGATEAREA 0.426000 ;
    PORT
      LAYER met2 ;
        RECT 648.690 1312.200 648.970 1316.200 ;
    END
  END W_DATA[30]
  PIN W_DATA[31]
    DIRECTION INPUT ;
    USE SIGNAL ;
    ANTENNAGATEAREA 0.426000 ;
    PORT
      LAYER met2 ;
        RECT 629.370 1312.200 629.650 1316.200 ;
    END
  END W_DATA[31]
  PIN W_DATA[3]
    DIRECTION INPUT ;
    USE SIGNAL ;
    ANTENNAGATEAREA 0.426000 ;
    PORT
      LAYER met2 ;
        RECT 1170.330 1312.200 1170.610 1316.200 ;
    END
  END W_DATA[3]
  PIN W_DATA[4]
    DIRECTION INPUT ;
    USE SIGNAL ;
    ANTENNAGATEAREA 0.426000 ;
    PORT
      LAYER met2 ;
        RECT 1151.010 1312.200 1151.290 1316.200 ;
    END
  END W_DATA[4]
  PIN W_DATA[5]
    DIRECTION INPUT ;
    USE SIGNAL ;
    ANTENNAGATEAREA 0.426000 ;
    PORT
      LAYER met2 ;
        RECT 1131.690 1312.200 1131.970 1316.200 ;
    END
  END W_DATA[5]
  PIN W_DATA[6]
    DIRECTION INPUT ;
    USE SIGNAL ;
    ANTENNAGATEAREA 0.247500 ;
    PORT
      LAYER met2 ;
        RECT 1112.370 1312.200 1112.650 1316.200 ;
    END
  END W_DATA[6]
  PIN W_DATA[7]
    DIRECTION INPUT ;
    USE SIGNAL ;
    ANTENNAGATEAREA 0.247500 ;
    PORT
      LAYER met2 ;
        RECT 1093.050 1312.200 1093.330 1316.200 ;
    END
  END W_DATA[7]
  PIN W_DATA[8]
    DIRECTION INPUT ;
    USE SIGNAL ;
    ANTENNAGATEAREA 0.247500 ;
    PORT
      LAYER met2 ;
        RECT 1073.730 1312.200 1074.010 1316.200 ;
    END
  END W_DATA[8]
  PIN W_DATA[9]
    DIRECTION INPUT ;
    USE SIGNAL ;
    ANTENNAGATEAREA 0.247500 ;
    PORT
      LAYER met2 ;
        RECT 1054.410 1312.200 1054.690 1316.200 ;
    END
  END W_DATA[9]
  PIN W_LEN[0]
    DIRECTION INPUT ;
    USE SIGNAL ;
    ANTENNAGATEAREA 0.247500 ;
    PORT
      LAYER met3 ;
        RECT 0.000 656.920 4.000 657.520 ;
    END
  END W_LEN[0]
  PIN W_LEN[1]
    DIRECTION INPUT ;
    USE SIGNAL ;
    ANTENNAGATEAREA 0.247500 ;
    PORT
      LAYER met3 ;
        RECT 0.000 609.320 4.000 609.920 ;
    END
  END W_LEN[1]
  PIN W_LEN[2]
    DIRECTION INPUT ;
    USE SIGNAL ;
    ANTENNAGATEAREA 0.247500 ;
    PORT
      LAYER met3 ;
        RECT 0.000 561.720 4.000 562.320 ;
    END
  END W_LEN[2]
  PIN W_LEN[3]
    DIRECTION INPUT ;
    USE SIGNAL ;
    ANTENNAGATEAREA 0.247500 ;
    PORT
      LAYER met3 ;
        RECT 0.000 514.120 4.000 514.720 ;
    END
  END W_LEN[3]
  PIN Y_OUT[0]
    DIRECTION OUTPUT ;
    USE SIGNAL ;
    ANTENNADIFFAREA 0.340600 ;
    PORT
      LAYER met2 ;
        RECT 1217.710 0.000 1217.990 4.000 ;
    END
  END Y_OUT[0]
  PIN Y_OUT[10]
    DIRECTION OUTPUT ;
    USE SIGNAL ;
    ANTENNADIFFAREA 0.340600 ;
    PORT
      LAYER met2 ;
        RECT 918.710 0.000 918.990 4.000 ;
    END
  END Y_OUT[10]
  PIN Y_OUT[11]
    DIRECTION OUTPUT ;
    USE SIGNAL ;
    ANTENNADIFFAREA 0.340600 ;
    PORT
      LAYER met2 ;
        RECT 888.810 0.000 889.090 4.000 ;
    END
  END Y_OUT[11]
  PIN Y_OUT[12]
    DIRECTION OUTPUT ;
    USE SIGNAL ;
    ANTENNADIFFAREA 0.340600 ;
    PORT
      LAYER met2 ;
        RECT 858.910 0.000 859.190 4.000 ;
    END
  END Y_OUT[12]
  PIN Y_OUT[13]
    DIRECTION OUTPUT ;
    USE SIGNAL ;
    ANTENNADIFFAREA 0.340600 ;
    PORT
      LAYER met2 ;
        RECT 829.010 0.000 829.290 4.000 ;
    END
  END Y_OUT[13]
  PIN Y_OUT[14]
    DIRECTION OUTPUT ;
    USE SIGNAL ;
    ANTENNADIFFAREA 0.340600 ;
    PORT
      LAYER met2 ;
        RECT 799.110 0.000 799.390 4.000 ;
    END
  END Y_OUT[14]
  PIN Y_OUT[15]
    DIRECTION OUTPUT ;
    USE SIGNAL ;
    ANTENNADIFFAREA 0.340600 ;
    PORT
      LAYER met2 ;
        RECT 769.210 0.000 769.490 4.000 ;
    END
  END Y_OUT[15]
  PIN Y_OUT[16]
    DIRECTION OUTPUT ;
    USE SIGNAL ;
    ANTENNADIFFAREA 0.340600 ;
    PORT
      LAYER met2 ;
        RECT 739.310 0.000 739.590 4.000 ;
    END
  END Y_OUT[16]
  PIN Y_OUT[17]
    DIRECTION OUTPUT ;
    USE SIGNAL ;
    ANTENNADIFFAREA 0.340600 ;
    PORT
      LAYER met2 ;
        RECT 709.410 0.000 709.690 4.000 ;
    END
  END Y_OUT[17]
  PIN Y_OUT[18]
    DIRECTION OUTPUT ;
    USE SIGNAL ;
    ANTENNADIFFAREA 0.340600 ;
    PORT
      LAYER met2 ;
        RECT 679.510 0.000 679.790 4.000 ;
    END
  END Y_OUT[18]
  PIN Y_OUT[19]
    DIRECTION OUTPUT ;
    USE SIGNAL ;
    ANTENNADIFFAREA 0.340600 ;
    PORT
      LAYER met2 ;
        RECT 649.610 0.000 649.890 4.000 ;
    END
  END Y_OUT[19]
  PIN Y_OUT[1]
    DIRECTION OUTPUT ;
    USE SIGNAL ;
    ANTENNADIFFAREA 0.340600 ;
    PORT
      LAYER met2 ;
        RECT 1187.810 0.000 1188.090 4.000 ;
    END
  END Y_OUT[1]
  PIN Y_OUT[20]
    DIRECTION OUTPUT ;
    USE SIGNAL ;
    ANTENNADIFFAREA 0.340600 ;
    PORT
      LAYER met2 ;
        RECT 619.710 0.000 619.990 4.000 ;
    END
  END Y_OUT[20]
  PIN Y_OUT[21]
    DIRECTION OUTPUT ;
    USE SIGNAL ;
    ANTENNADIFFAREA 0.340600 ;
    PORT
      LAYER met2 ;
        RECT 589.810 0.000 590.090 4.000 ;
    END
  END Y_OUT[21]
  PIN Y_OUT[22]
    DIRECTION OUTPUT ;
    USE SIGNAL ;
    ANTENNADIFFAREA 0.340600 ;
    PORT
      LAYER met2 ;
        RECT 559.910 0.000 560.190 4.000 ;
    END
  END Y_OUT[22]
  PIN Y_OUT[23]
    DIRECTION OUTPUT ;
    USE SIGNAL ;
    ANTENNADIFFAREA 0.340600 ;
    PORT
      LAYER met2 ;
        RECT 530.010 0.000 530.290 4.000 ;
    END
  END Y_OUT[23]
  PIN Y_OUT[24]
    DIRECTION OUTPUT ;
    USE SIGNAL ;
    ANTENNADIFFAREA 0.340600 ;
    PORT
      LAYER met2 ;
        RECT 500.110 0.000 500.390 4.000 ;
    END
  END Y_OUT[24]
  PIN Y_OUT[25]
    DIRECTION OUTPUT ;
    USE SIGNAL ;
    ANTENNADIFFAREA 0.340600 ;
    PORT
      LAYER met2 ;
        RECT 470.210 0.000 470.490 4.000 ;
    END
  END Y_OUT[25]
  PIN Y_OUT[26]
    DIRECTION OUTPUT ;
    USE SIGNAL ;
    ANTENNADIFFAREA 0.340600 ;
    PORT
      LAYER met2 ;
        RECT 440.310 0.000 440.590 4.000 ;
    END
  END Y_OUT[26]
  PIN Y_OUT[27]
    DIRECTION OUTPUT ;
    USE SIGNAL ;
    ANTENNADIFFAREA 0.340600 ;
    PORT
      LAYER met2 ;
        RECT 410.410 0.000 410.690 4.000 ;
    END
  END Y_OUT[27]
  PIN Y_OUT[28]
    DIRECTION OUTPUT ;
    USE SIGNAL ;
    ANTENNADIFFAREA 0.340600 ;
    PORT
      LAYER met2 ;
        RECT 380.510 0.000 380.790 4.000 ;
    END
  END Y_OUT[28]
  PIN Y_OUT[29]
    DIRECTION OUTPUT ;
    USE SIGNAL ;
    ANTENNADIFFAREA 0.340600 ;
    PORT
      LAYER met2 ;
        RECT 350.610 0.000 350.890 4.000 ;
    END
  END Y_OUT[29]
  PIN Y_OUT[2]
    DIRECTION OUTPUT ;
    USE SIGNAL ;
    ANTENNADIFFAREA 0.340600 ;
    PORT
      LAYER met2 ;
        RECT 1157.910 0.000 1158.190 4.000 ;
    END
  END Y_OUT[2]
  PIN Y_OUT[30]
    DIRECTION OUTPUT ;
    USE SIGNAL ;
    ANTENNADIFFAREA 0.340600 ;
    PORT
      LAYER met2 ;
        RECT 320.710 0.000 320.990 4.000 ;
    END
  END Y_OUT[30]
  PIN Y_OUT[31]
    DIRECTION OUTPUT ;
    USE SIGNAL ;
    ANTENNADIFFAREA 0.340600 ;
    PORT
      LAYER met2 ;
        RECT 290.810 0.000 291.090 4.000 ;
    END
  END Y_OUT[31]
  PIN Y_OUT[3]
    DIRECTION OUTPUT ;
    USE SIGNAL ;
    ANTENNADIFFAREA 0.340600 ;
    PORT
      LAYER met2 ;
        RECT 1128.010 0.000 1128.290 4.000 ;
    END
  END Y_OUT[3]
  PIN Y_OUT[4]
    DIRECTION OUTPUT ;
    USE SIGNAL ;
    ANTENNADIFFAREA 0.340600 ;
    PORT
      LAYER met2 ;
        RECT 1098.110 0.000 1098.390 4.000 ;
    END
  END Y_OUT[4]
  PIN Y_OUT[5]
    DIRECTION OUTPUT ;
    USE SIGNAL ;
    ANTENNADIFFAREA 0.340600 ;
    PORT
      LAYER met2 ;
        RECT 1068.210 0.000 1068.490 4.000 ;
    END
  END Y_OUT[5]
  PIN Y_OUT[6]
    DIRECTION OUTPUT ;
    USE SIGNAL ;
    ANTENNADIFFAREA 0.340600 ;
    PORT
      LAYER met2 ;
        RECT 1038.310 0.000 1038.590 4.000 ;
    END
  END Y_OUT[6]
  PIN Y_OUT[7]
    DIRECTION OUTPUT ;
    USE SIGNAL ;
    ANTENNADIFFAREA 0.340600 ;
    PORT
      LAYER met2 ;
        RECT 1008.410 0.000 1008.690 4.000 ;
    END
  END Y_OUT[7]
  PIN Y_OUT[8]
    DIRECTION OUTPUT ;
    USE SIGNAL ;
    ANTENNADIFFAREA 0.340600 ;
    PORT
      LAYER met2 ;
        RECT 978.510 0.000 978.790 4.000 ;
    END
  END Y_OUT[8]
  PIN Y_OUT[9]
    DIRECTION OUTPUT ;
    USE SIGNAL ;
    ANTENNADIFFAREA 0.340600 ;
    PORT
      LAYER met2 ;
        RECT 948.610 0.000 948.890 4.000 ;
    END
  END Y_OUT[9]
  PIN Y_RDY
    DIRECTION INPUT ;
    USE SIGNAL ;
    ANTENNAGATEAREA 0.247500 ;
    PORT
      LAYER met2 ;
        RECT 21.710 0.000 21.990 4.000 ;
    END
  END Y_RDY
  PIN Y_VLD[0]
    DIRECTION OUTPUT ;
    USE SIGNAL ;
    ANTENNADIFFAREA 0.340600 ;
    PORT
      LAYER met2 ;
        RECT 260.910 0.000 261.190 4.000 ;
    END
  END Y_VLD[0]
  PIN Y_VLD[1]
    DIRECTION OUTPUT ;
    USE SIGNAL ;
    ANTENNADIFFAREA 0.340600 ;
    PORT
      LAYER met2 ;
        RECT 231.010 0.000 231.290 4.000 ;
    END
  END Y_VLD[1]
  PIN Y_VLD[2]
    DIRECTION OUTPUT ;
    USE SIGNAL ;
    ANTENNADIFFAREA 0.340600 ;
    PORT
      LAYER met2 ;
        RECT 201.110 0.000 201.390 4.000 ;
    END
  END Y_VLD[2]
  PIN Y_VLD[3]
    DIRECTION OUTPUT ;
    USE SIGNAL ;
    ANTENNADIFFAREA 0.340600 ;
    PORT
      LAYER met2 ;
        RECT 171.210 0.000 171.490 4.000 ;
    END
  END Y_VLD[3]
  PIN Y_VLD[4]
    DIRECTION OUTPUT ;
    USE SIGNAL ;
    ANTENNADIFFAREA 0.340600 ;
    PORT
      LAYER met2 ;
        RECT 141.310 0.000 141.590 4.000 ;
    END
  END Y_VLD[4]
  PIN Y_VLD[5]
    DIRECTION OUTPUT ;
    USE SIGNAL ;
    ANTENNADIFFAREA 0.340600 ;
    PORT
      LAYER met2 ;
        RECT 111.410 0.000 111.690 4.000 ;
    END
  END Y_VLD[5]
  PIN Y_VLD[6]
    DIRECTION OUTPUT ;
    USE SIGNAL ;
    ANTENNADIFFAREA 0.340600 ;
    PORT
      LAYER met2 ;
        RECT 81.510 0.000 81.790 4.000 ;
    END
  END Y_VLD[6]
  PIN Y_VLD[7]
    DIRECTION OUTPUT ;
    USE SIGNAL ;
    ANTENNADIFFAREA 0.340600 ;
    PORT
      LAYER met2 ;
        RECT 51.610 0.000 51.890 4.000 ;
    END
  END Y_VLD[7]
  PIN clk
    DIRECTION INPUT ;
    USE SIGNAL ;
    ANTENNAGATEAREA 1.704000 ;
    PORT
      LAYER met3 ;
        RECT 0.000 38.120 4.000 38.720 ;
    END
  END clk
  PIN rst_n
    DIRECTION INPUT ;
    USE SIGNAL ;
    ANTENNAGATEAREA 0.852000 ;
    PORT
      LAYER met3 ;
        RECT 0.000 85.720 4.000 86.320 ;
    END
  END rst_n
  OBS
      LAYER nwell ;
        RECT 9.930 10.795 1229.770 1305.685 ;
      LAYER li1 ;
        RECT 10.120 10.795 1229.580 1305.685 ;
      LAYER met1 ;
        RECT 0.070 10.240 1229.580 1311.000 ;
      LAYER met2 ;
        RECT 0.100 1311.920 10.850 1312.810 ;
        RECT 11.690 1311.920 30.170 1312.810 ;
        RECT 31.010 1311.920 49.490 1312.810 ;
        RECT 50.330 1311.920 68.810 1312.810 ;
        RECT 69.650 1311.920 88.130 1312.810 ;
        RECT 88.970 1311.920 107.450 1312.810 ;
        RECT 108.290 1311.920 126.770 1312.810 ;
        RECT 127.610 1311.920 146.090 1312.810 ;
        RECT 146.930 1311.920 165.410 1312.810 ;
        RECT 166.250 1311.920 184.730 1312.810 ;
        RECT 185.570 1311.920 204.050 1312.810 ;
        RECT 204.890 1311.920 223.370 1312.810 ;
        RECT 224.210 1311.920 242.690 1312.810 ;
        RECT 243.530 1311.920 262.010 1312.810 ;
        RECT 262.850 1311.920 281.330 1312.810 ;
        RECT 282.170 1311.920 300.650 1312.810 ;
        RECT 301.490 1311.920 319.970 1312.810 ;
        RECT 320.810 1311.920 339.290 1312.810 ;
        RECT 340.130 1311.920 358.610 1312.810 ;
        RECT 359.450 1311.920 377.930 1312.810 ;
        RECT 378.770 1311.920 397.250 1312.810 ;
        RECT 398.090 1311.920 416.570 1312.810 ;
        RECT 417.410 1311.920 435.890 1312.810 ;
        RECT 436.730 1311.920 455.210 1312.810 ;
        RECT 456.050 1311.920 474.530 1312.810 ;
        RECT 475.370 1311.920 493.850 1312.810 ;
        RECT 494.690 1311.920 513.170 1312.810 ;
        RECT 514.010 1311.920 532.490 1312.810 ;
        RECT 533.330 1311.920 551.810 1312.810 ;
        RECT 552.650 1311.920 571.130 1312.810 ;
        RECT 571.970 1311.920 590.450 1312.810 ;
        RECT 591.290 1311.920 609.770 1312.810 ;
        RECT 610.610 1311.920 629.090 1312.810 ;
        RECT 629.930 1311.920 648.410 1312.810 ;
        RECT 649.250 1311.920 667.730 1312.810 ;
        RECT 668.570 1311.920 687.050 1312.810 ;
        RECT 687.890 1311.920 706.370 1312.810 ;
        RECT 707.210 1311.920 725.690 1312.810 ;
        RECT 726.530 1311.920 745.010 1312.810 ;
        RECT 745.850 1311.920 764.330 1312.810 ;
        RECT 765.170 1311.920 783.650 1312.810 ;
        RECT 784.490 1311.920 802.970 1312.810 ;
        RECT 803.810 1311.920 822.290 1312.810 ;
        RECT 823.130 1311.920 841.610 1312.810 ;
        RECT 842.450 1311.920 860.930 1312.810 ;
        RECT 861.770 1311.920 880.250 1312.810 ;
        RECT 881.090 1311.920 899.570 1312.810 ;
        RECT 900.410 1311.920 918.890 1312.810 ;
        RECT 919.730 1311.920 938.210 1312.810 ;
        RECT 939.050 1311.920 957.530 1312.810 ;
        RECT 958.370 1311.920 976.850 1312.810 ;
        RECT 977.690 1311.920 996.170 1312.810 ;
        RECT 997.010 1311.920 1015.490 1312.810 ;
        RECT 1016.330 1311.920 1034.810 1312.810 ;
        RECT 1035.650 1311.920 1054.130 1312.810 ;
        RECT 1054.970 1311.920 1073.450 1312.810 ;
        RECT 1074.290 1311.920 1092.770 1312.810 ;
        RECT 1093.610 1311.920 1112.090 1312.810 ;
        RECT 1112.930 1311.920 1131.410 1312.810 ;
        RECT 1132.250 1311.920 1150.730 1312.810 ;
        RECT 1151.570 1311.920 1170.050 1312.810 ;
        RECT 1170.890 1311.920 1189.370 1312.810 ;
        RECT 1190.210 1311.920 1208.690 1312.810 ;
        RECT 1209.530 1311.920 1228.010 1312.810 ;
        RECT 1228.850 1311.920 1229.030 1312.810 ;
        RECT 0.100 4.280 1229.030 1311.920 ;
        RECT 0.100 4.000 21.430 4.280 ;
        RECT 22.270 4.000 51.330 4.280 ;
        RECT 52.170 4.000 81.230 4.280 ;
        RECT 82.070 4.000 111.130 4.280 ;
        RECT 111.970 4.000 141.030 4.280 ;
        RECT 141.870 4.000 170.930 4.280 ;
        RECT 171.770 4.000 200.830 4.280 ;
        RECT 201.670 4.000 230.730 4.280 ;
        RECT 231.570 4.000 260.630 4.280 ;
        RECT 261.470 4.000 290.530 4.280 ;
        RECT 291.370 4.000 320.430 4.280 ;
        RECT 321.270 4.000 350.330 4.280 ;
        RECT 351.170 4.000 380.230 4.280 ;
        RECT 381.070 4.000 410.130 4.280 ;
        RECT 410.970 4.000 440.030 4.280 ;
        RECT 440.870 4.000 469.930 4.280 ;
        RECT 470.770 4.000 499.830 4.280 ;
        RECT 500.670 4.000 529.730 4.280 ;
        RECT 530.570 4.000 559.630 4.280 ;
        RECT 560.470 4.000 589.530 4.280 ;
        RECT 590.370 4.000 619.430 4.280 ;
        RECT 620.270 4.000 649.330 4.280 ;
        RECT 650.170 4.000 679.230 4.280 ;
        RECT 680.070 4.000 709.130 4.280 ;
        RECT 709.970 4.000 739.030 4.280 ;
        RECT 739.870 4.000 768.930 4.280 ;
        RECT 769.770 4.000 798.830 4.280 ;
        RECT 799.670 4.000 828.730 4.280 ;
        RECT 829.570 4.000 858.630 4.280 ;
        RECT 859.470 4.000 888.530 4.280 ;
        RECT 889.370 4.000 918.430 4.280 ;
        RECT 919.270 4.000 948.330 4.280 ;
        RECT 949.170 4.000 978.230 4.280 ;
        RECT 979.070 4.000 1008.130 4.280 ;
        RECT 1008.970 4.000 1038.030 4.280 ;
        RECT 1038.870 4.000 1067.930 4.280 ;
        RECT 1068.770 4.000 1097.830 4.280 ;
        RECT 1098.670 4.000 1127.730 4.280 ;
        RECT 1128.570 4.000 1157.630 4.280 ;
        RECT 1158.470 4.000 1187.530 4.280 ;
        RECT 1188.370 4.000 1217.430 4.280 ;
        RECT 1218.270 4.000 1229.030 4.280 ;
      LAYER met3 ;
        RECT 0.525 1290.320 1236.000 1308.145 ;
        RECT 0.525 1288.920 1235.600 1290.320 ;
        RECT 0.525 1276.720 1236.000 1288.920 ;
        RECT 4.400 1275.320 1236.000 1276.720 ;
        RECT 0.525 1249.520 1236.000 1275.320 ;
        RECT 0.525 1248.120 1235.600 1249.520 ;
        RECT 0.525 1229.120 1236.000 1248.120 ;
        RECT 4.400 1227.720 1236.000 1229.120 ;
        RECT 0.525 1208.720 1236.000 1227.720 ;
        RECT 0.525 1207.320 1235.600 1208.720 ;
        RECT 0.525 1181.520 1236.000 1207.320 ;
        RECT 4.400 1180.120 1236.000 1181.520 ;
        RECT 0.525 1167.920 1236.000 1180.120 ;
        RECT 0.525 1166.520 1235.600 1167.920 ;
        RECT 0.525 1133.920 1236.000 1166.520 ;
        RECT 4.400 1132.520 1236.000 1133.920 ;
        RECT 0.525 1127.120 1236.000 1132.520 ;
        RECT 0.525 1125.720 1235.600 1127.120 ;
        RECT 0.525 1086.320 1236.000 1125.720 ;
        RECT 4.400 1084.920 1235.600 1086.320 ;
        RECT 0.525 1045.520 1236.000 1084.920 ;
        RECT 0.525 1044.120 1235.600 1045.520 ;
        RECT 0.525 1038.720 1236.000 1044.120 ;
        RECT 4.400 1037.320 1236.000 1038.720 ;
        RECT 0.525 1004.720 1236.000 1037.320 ;
        RECT 0.525 1003.320 1235.600 1004.720 ;
        RECT 0.525 991.120 1236.000 1003.320 ;
        RECT 4.400 989.720 1236.000 991.120 ;
        RECT 0.525 963.920 1236.000 989.720 ;
        RECT 0.525 962.520 1235.600 963.920 ;
        RECT 0.525 943.520 1236.000 962.520 ;
        RECT 4.400 942.120 1236.000 943.520 ;
        RECT 0.525 923.120 1236.000 942.120 ;
        RECT 0.525 921.720 1235.600 923.120 ;
        RECT 0.525 895.920 1236.000 921.720 ;
        RECT 4.400 894.520 1236.000 895.920 ;
        RECT 0.525 882.320 1236.000 894.520 ;
        RECT 0.525 880.920 1235.600 882.320 ;
        RECT 0.525 848.320 1236.000 880.920 ;
        RECT 4.400 846.920 1236.000 848.320 ;
        RECT 0.525 841.520 1236.000 846.920 ;
        RECT 0.525 840.120 1235.600 841.520 ;
        RECT 0.525 800.720 1236.000 840.120 ;
        RECT 4.400 799.320 1235.600 800.720 ;
        RECT 0.525 759.920 1236.000 799.320 ;
        RECT 0.525 758.520 1235.600 759.920 ;
        RECT 0.525 753.120 1236.000 758.520 ;
        RECT 4.400 751.720 1236.000 753.120 ;
        RECT 0.525 719.120 1236.000 751.720 ;
        RECT 0.525 717.720 1235.600 719.120 ;
        RECT 0.525 705.520 1236.000 717.720 ;
        RECT 4.400 704.120 1236.000 705.520 ;
        RECT 0.525 678.320 1236.000 704.120 ;
        RECT 0.525 676.920 1235.600 678.320 ;
        RECT 0.525 657.920 1236.000 676.920 ;
        RECT 4.400 656.520 1236.000 657.920 ;
        RECT 0.525 637.520 1236.000 656.520 ;
        RECT 0.525 636.120 1235.600 637.520 ;
        RECT 0.525 610.320 1236.000 636.120 ;
        RECT 4.400 608.920 1236.000 610.320 ;
        RECT 0.525 596.720 1236.000 608.920 ;
        RECT 0.525 595.320 1235.600 596.720 ;
        RECT 0.525 562.720 1236.000 595.320 ;
        RECT 4.400 561.320 1236.000 562.720 ;
        RECT 0.525 555.920 1236.000 561.320 ;
        RECT 0.525 554.520 1235.600 555.920 ;
        RECT 0.525 515.120 1236.000 554.520 ;
        RECT 4.400 513.720 1235.600 515.120 ;
        RECT 0.525 474.320 1236.000 513.720 ;
        RECT 0.525 472.920 1235.600 474.320 ;
        RECT 0.525 467.520 1236.000 472.920 ;
        RECT 4.400 466.120 1236.000 467.520 ;
        RECT 0.525 433.520 1236.000 466.120 ;
        RECT 0.525 432.120 1235.600 433.520 ;
        RECT 0.525 419.920 1236.000 432.120 ;
        RECT 4.400 418.520 1236.000 419.920 ;
        RECT 0.525 392.720 1236.000 418.520 ;
        RECT 0.525 391.320 1235.600 392.720 ;
        RECT 0.525 372.320 1236.000 391.320 ;
        RECT 4.400 370.920 1236.000 372.320 ;
        RECT 0.525 351.920 1236.000 370.920 ;
        RECT 0.525 350.520 1235.600 351.920 ;
        RECT 0.525 324.720 1236.000 350.520 ;
        RECT 4.400 323.320 1236.000 324.720 ;
        RECT 0.525 311.120 1236.000 323.320 ;
        RECT 0.525 309.720 1235.600 311.120 ;
        RECT 0.525 277.120 1236.000 309.720 ;
        RECT 4.400 275.720 1236.000 277.120 ;
        RECT 0.525 270.320 1236.000 275.720 ;
        RECT 0.525 268.920 1235.600 270.320 ;
        RECT 0.525 229.520 1236.000 268.920 ;
        RECT 4.400 228.120 1235.600 229.520 ;
        RECT 0.525 188.720 1236.000 228.120 ;
        RECT 0.525 187.320 1235.600 188.720 ;
        RECT 0.525 181.920 1236.000 187.320 ;
        RECT 4.400 180.520 1236.000 181.920 ;
        RECT 0.525 147.920 1236.000 180.520 ;
        RECT 0.525 146.520 1235.600 147.920 ;
        RECT 0.525 134.320 1236.000 146.520 ;
        RECT 4.400 132.920 1236.000 134.320 ;
        RECT 0.525 107.120 1236.000 132.920 ;
        RECT 0.525 105.720 1235.600 107.120 ;
        RECT 0.525 86.720 1236.000 105.720 ;
        RECT 4.400 85.320 1236.000 86.720 ;
        RECT 0.525 66.320 1236.000 85.320 ;
        RECT 0.525 64.920 1235.600 66.320 ;
        RECT 0.525 39.120 1236.000 64.920 ;
        RECT 4.400 37.720 1236.000 39.120 ;
        RECT 0.525 25.520 1236.000 37.720 ;
        RECT 0.525 24.120 1235.600 25.520 ;
        RECT 0.525 10.715 1236.000 24.120 ;
      LAYER met4 ;
        RECT 3.055 1306.240 1213.185 1308.145 ;
        RECT 3.055 1265.440 180.455 1306.240 ;
        RECT 3.055 1130.880 23.180 1265.440 ;
        RECT 25.580 1130.880 26.860 1265.440 ;
        RECT 29.260 1262.720 180.455 1265.440 ;
        RECT 29.260 1130.880 175.900 1262.720 ;
        RECT 178.300 1130.880 180.455 1262.720 ;
        RECT 3.055 1121.280 180.455 1130.880 ;
        RECT 3.055 986.720 23.180 1121.280 ;
        RECT 25.580 986.720 26.860 1121.280 ;
        RECT 29.260 989.440 175.900 1121.280 ;
        RECT 178.300 989.440 180.455 1121.280 ;
        RECT 29.260 986.720 180.455 989.440 ;
        RECT 3.055 977.120 180.455 986.720 ;
        RECT 3.055 842.560 23.180 977.120 ;
        RECT 25.580 842.560 26.860 977.120 ;
        RECT 29.260 974.400 180.455 977.120 ;
        RECT 29.260 842.560 175.900 974.400 ;
        RECT 178.300 842.560 180.455 974.400 ;
        RECT 3.055 832.960 180.455 842.560 ;
        RECT 3.055 698.400 23.180 832.960 ;
        RECT 25.580 698.400 26.860 832.960 ;
        RECT 29.260 701.120 175.900 832.960 ;
        RECT 178.300 701.120 180.455 832.960 ;
        RECT 29.260 698.400 180.455 701.120 ;
        RECT 3.055 688.800 180.455 698.400 ;
        RECT 3.055 554.240 23.180 688.800 ;
        RECT 25.580 554.240 26.860 688.800 ;
        RECT 29.260 686.080 180.455 688.800 ;
        RECT 29.260 554.240 175.900 686.080 ;
        RECT 178.300 554.240 180.455 686.080 ;
        RECT 3.055 544.640 180.455 554.240 ;
        RECT 3.055 410.080 23.180 544.640 ;
        RECT 25.580 410.080 26.860 544.640 ;
        RECT 29.260 412.800 175.900 544.640 ;
        RECT 178.300 412.800 180.455 544.640 ;
        RECT 29.260 410.080 180.455 412.800 ;
        RECT 3.055 400.480 180.455 410.080 ;
        RECT 3.055 265.920 23.180 400.480 ;
        RECT 25.580 265.920 26.860 400.480 ;
        RECT 29.260 397.760 180.455 400.480 ;
        RECT 29.260 265.920 175.900 397.760 ;
        RECT 178.300 265.920 180.455 397.760 ;
        RECT 3.055 256.320 180.455 265.920 ;
        RECT 3.055 121.760 23.180 256.320 ;
        RECT 25.580 121.760 26.860 256.320 ;
        RECT 29.260 124.480 175.900 256.320 ;
        RECT 178.300 124.480 180.455 256.320 ;
        RECT 29.260 121.760 180.455 124.480 ;
        RECT 3.055 87.680 180.455 121.760 ;
        RECT 3.055 70.080 16.740 87.680 ;
        RECT 19.140 70.080 20.420 87.680 ;
        RECT 22.820 77.725 180.455 87.680 ;
        RECT 182.855 77.725 183.755 1306.240 ;
        RECT 186.155 1262.720 324.785 1306.240 ;
        RECT 186.155 1130.880 320.340 1262.720 ;
        RECT 322.740 1130.880 324.785 1262.720 ;
        RECT 186.155 1121.280 324.785 1130.880 ;
        RECT 186.155 989.440 320.340 1121.280 ;
        RECT 322.740 989.440 324.785 1121.280 ;
        RECT 186.155 974.400 324.785 989.440 ;
        RECT 186.155 842.560 320.340 974.400 ;
        RECT 322.740 842.560 324.785 974.400 ;
        RECT 186.155 832.960 324.785 842.560 ;
        RECT 186.155 701.120 320.340 832.960 ;
        RECT 322.740 701.120 324.785 832.960 ;
        RECT 186.155 686.080 324.785 701.120 ;
        RECT 186.155 554.240 320.340 686.080 ;
        RECT 322.740 554.240 324.785 686.080 ;
        RECT 186.155 544.640 324.785 554.240 ;
        RECT 186.155 412.800 320.340 544.640 ;
        RECT 322.740 412.800 324.785 544.640 ;
        RECT 186.155 397.760 324.785 412.800 ;
        RECT 186.155 265.920 320.340 397.760 ;
        RECT 322.740 265.920 324.785 397.760 ;
        RECT 186.155 256.320 324.785 265.920 ;
        RECT 186.155 124.480 320.340 256.320 ;
        RECT 322.740 124.480 324.785 256.320 ;
        RECT 186.155 77.725 324.785 124.480 ;
        RECT 327.185 77.725 328.085 1306.240 ;
        RECT 330.485 1262.720 469.115 1306.240 ;
        RECT 330.485 1130.880 464.780 1262.720 ;
        RECT 467.180 1130.880 469.115 1262.720 ;
        RECT 330.485 1121.280 469.115 1130.880 ;
        RECT 330.485 989.440 464.780 1121.280 ;
        RECT 467.180 989.440 469.115 1121.280 ;
        RECT 330.485 974.400 469.115 989.440 ;
        RECT 330.485 842.560 464.780 974.400 ;
        RECT 467.180 842.560 469.115 974.400 ;
        RECT 330.485 832.960 469.115 842.560 ;
        RECT 330.485 701.120 464.780 832.960 ;
        RECT 467.180 701.120 469.115 832.960 ;
        RECT 330.485 686.080 469.115 701.120 ;
        RECT 330.485 554.240 464.780 686.080 ;
        RECT 467.180 554.240 469.115 686.080 ;
        RECT 330.485 544.640 469.115 554.240 ;
        RECT 330.485 412.800 464.780 544.640 ;
        RECT 467.180 412.800 469.115 544.640 ;
        RECT 330.485 397.760 469.115 412.800 ;
        RECT 330.485 265.920 464.780 397.760 ;
        RECT 467.180 265.920 469.115 397.760 ;
        RECT 330.485 256.320 469.115 265.920 ;
        RECT 330.485 124.480 464.780 256.320 ;
        RECT 467.180 124.480 469.115 256.320 ;
        RECT 330.485 77.725 469.115 124.480 ;
        RECT 471.515 77.725 472.415 1306.240 ;
        RECT 474.815 1262.720 613.445 1306.240 ;
        RECT 474.815 1130.880 609.220 1262.720 ;
        RECT 611.620 1130.880 613.445 1262.720 ;
        RECT 474.815 1121.280 613.445 1130.880 ;
        RECT 474.815 989.440 609.220 1121.280 ;
        RECT 611.620 989.440 613.445 1121.280 ;
        RECT 474.815 974.400 613.445 989.440 ;
        RECT 474.815 842.560 609.220 974.400 ;
        RECT 611.620 842.560 613.445 974.400 ;
        RECT 474.815 832.960 613.445 842.560 ;
        RECT 474.815 701.120 609.220 832.960 ;
        RECT 611.620 701.120 613.445 832.960 ;
        RECT 474.815 686.080 613.445 701.120 ;
        RECT 474.815 554.240 609.220 686.080 ;
        RECT 611.620 554.240 613.445 686.080 ;
        RECT 474.815 544.640 613.445 554.240 ;
        RECT 474.815 412.800 609.220 544.640 ;
        RECT 611.620 412.800 613.445 544.640 ;
        RECT 474.815 397.760 613.445 412.800 ;
        RECT 474.815 265.920 609.220 397.760 ;
        RECT 611.620 265.920 613.445 397.760 ;
        RECT 474.815 256.320 613.445 265.920 ;
        RECT 474.815 124.480 609.220 256.320 ;
        RECT 611.620 124.480 613.445 256.320 ;
        RECT 474.815 77.725 613.445 124.480 ;
        RECT 615.845 77.725 616.745 1306.240 ;
        RECT 619.145 1262.720 757.775 1306.240 ;
        RECT 619.145 1130.880 753.660 1262.720 ;
        RECT 756.060 1130.880 757.775 1262.720 ;
        RECT 619.145 1121.280 757.775 1130.880 ;
        RECT 619.145 989.440 753.660 1121.280 ;
        RECT 756.060 989.440 757.775 1121.280 ;
        RECT 619.145 974.400 757.775 989.440 ;
        RECT 619.145 842.560 753.660 974.400 ;
        RECT 756.060 842.560 757.775 974.400 ;
        RECT 619.145 832.960 757.775 842.560 ;
        RECT 619.145 701.120 753.660 832.960 ;
        RECT 756.060 701.120 757.775 832.960 ;
        RECT 619.145 686.080 757.775 701.120 ;
        RECT 619.145 554.240 753.660 686.080 ;
        RECT 756.060 554.240 757.775 686.080 ;
        RECT 619.145 544.640 757.775 554.240 ;
        RECT 619.145 412.800 753.660 544.640 ;
        RECT 756.060 412.800 757.775 544.640 ;
        RECT 619.145 397.760 757.775 412.800 ;
        RECT 619.145 265.920 753.660 397.760 ;
        RECT 756.060 265.920 757.775 397.760 ;
        RECT 619.145 256.320 757.775 265.920 ;
        RECT 619.145 124.480 753.660 256.320 ;
        RECT 756.060 124.480 757.775 256.320 ;
        RECT 619.145 77.725 757.775 124.480 ;
        RECT 760.175 77.725 761.075 1306.240 ;
        RECT 763.475 1262.720 902.105 1306.240 ;
        RECT 763.475 1130.880 898.100 1262.720 ;
        RECT 900.500 1130.880 902.105 1262.720 ;
        RECT 763.475 1121.280 902.105 1130.880 ;
        RECT 763.475 989.440 898.100 1121.280 ;
        RECT 900.500 989.440 902.105 1121.280 ;
        RECT 763.475 974.400 902.105 989.440 ;
        RECT 763.475 842.560 898.100 974.400 ;
        RECT 900.500 842.560 902.105 974.400 ;
        RECT 763.475 832.960 902.105 842.560 ;
        RECT 763.475 701.120 898.100 832.960 ;
        RECT 900.500 701.120 902.105 832.960 ;
        RECT 763.475 686.080 902.105 701.120 ;
        RECT 763.475 554.240 898.100 686.080 ;
        RECT 900.500 554.240 902.105 686.080 ;
        RECT 763.475 544.640 902.105 554.240 ;
        RECT 763.475 412.800 898.100 544.640 ;
        RECT 900.500 412.800 902.105 544.640 ;
        RECT 763.475 397.760 902.105 412.800 ;
        RECT 763.475 265.920 898.100 397.760 ;
        RECT 900.500 265.920 902.105 397.760 ;
        RECT 763.475 256.320 902.105 265.920 ;
        RECT 763.475 124.480 898.100 256.320 ;
        RECT 900.500 124.480 902.105 256.320 ;
        RECT 763.475 77.725 902.105 124.480 ;
        RECT 904.505 77.725 905.405 1306.240 ;
        RECT 907.805 1262.720 1046.435 1306.240 ;
        RECT 907.805 1130.880 1042.540 1262.720 ;
        RECT 1044.940 1130.880 1046.435 1262.720 ;
        RECT 907.805 1121.280 1046.435 1130.880 ;
        RECT 907.805 989.440 1042.540 1121.280 ;
        RECT 1044.940 989.440 1046.435 1121.280 ;
        RECT 907.805 974.400 1046.435 989.440 ;
        RECT 907.805 842.560 1042.540 974.400 ;
        RECT 1044.940 842.560 1046.435 974.400 ;
        RECT 907.805 832.960 1046.435 842.560 ;
        RECT 907.805 701.120 1042.540 832.960 ;
        RECT 1044.940 701.120 1046.435 832.960 ;
        RECT 907.805 686.080 1046.435 701.120 ;
        RECT 907.805 554.240 1042.540 686.080 ;
        RECT 1044.940 554.240 1046.435 686.080 ;
        RECT 907.805 544.640 1046.435 554.240 ;
        RECT 907.805 412.800 1042.540 544.640 ;
        RECT 1044.940 412.800 1046.435 544.640 ;
        RECT 907.805 397.760 1046.435 412.800 ;
        RECT 907.805 265.920 1042.540 397.760 ;
        RECT 1044.940 265.920 1046.435 397.760 ;
        RECT 907.805 256.320 1046.435 265.920 ;
        RECT 907.805 124.480 1042.540 256.320 ;
        RECT 1044.940 124.480 1046.435 256.320 ;
        RECT 907.805 77.725 1046.435 124.480 ;
        RECT 1048.835 77.725 1049.735 1306.240 ;
        RECT 1052.135 77.725 1190.765 1306.240 ;
        RECT 22.820 70.880 1190.765 77.725 ;
        RECT 22.820 70.080 23.180 70.880 ;
        RECT 3.055 26.560 23.180 70.080 ;
        RECT 25.580 30.560 26.860 70.880 ;
        RECT 29.260 30.560 1190.765 70.880 ;
        RECT 25.580 26.560 25.940 30.560 ;
        RECT 29.260 30.060 29.620 30.560 ;
        RECT 3.055 14.455 25.940 26.560 ;
        RECT 28.340 14.455 29.620 30.060 ;
        RECT 32.020 19.515 1190.765 30.560 ;
        RECT 32.020 14.455 180.455 19.515 ;
        RECT 182.855 14.455 183.755 19.515 ;
        RECT 186.155 14.455 324.785 19.515 ;
        RECT 327.185 14.455 328.085 19.515 ;
        RECT 330.485 14.455 469.115 19.515 ;
        RECT 471.515 14.455 472.415 19.515 ;
        RECT 474.815 14.455 613.445 19.515 ;
        RECT 615.845 14.455 616.745 19.515 ;
        RECT 619.145 14.455 757.775 19.515 ;
        RECT 760.175 14.455 761.075 19.515 ;
        RECT 763.475 14.455 902.105 19.515 ;
        RECT 904.505 14.455 905.405 19.515 ;
        RECT 907.805 14.455 1046.435 19.515 ;
        RECT 1048.835 14.455 1049.735 19.515 ;
        RECT 1052.135 14.455 1190.765 19.515 ;
        RECT 1193.165 14.455 1194.065 1306.240 ;
        RECT 1196.465 79.520 1213.185 1306.240 ;
        RECT 1196.465 21.120 1210.900 79.520 ;
        RECT 1196.465 14.455 1213.185 21.120 ;
      LAYER met5 ;
        RECT 11.620 1176.660 1191.040 1304.700 ;
        RECT 11.620 1037.940 1191.040 1168.560 ;
        RECT 11.620 899.220 1191.040 1029.840 ;
        RECT 11.620 760.500 1191.040 891.120 ;
        RECT 11.620 621.780 1191.040 752.400 ;
        RECT 11.620 483.060 1191.040 613.680 ;
        RECT 11.620 344.340 1191.040 474.960 ;
        RECT 11.620 205.620 1191.040 336.240 ;
        RECT 11.620 66.900 1191.040 197.520 ;
        RECT 11.620 58.800 1098.100 66.900 ;
        RECT 11.620 31.500 1191.040 58.800 ;
  END
END gemm_top
END LIBRARY

